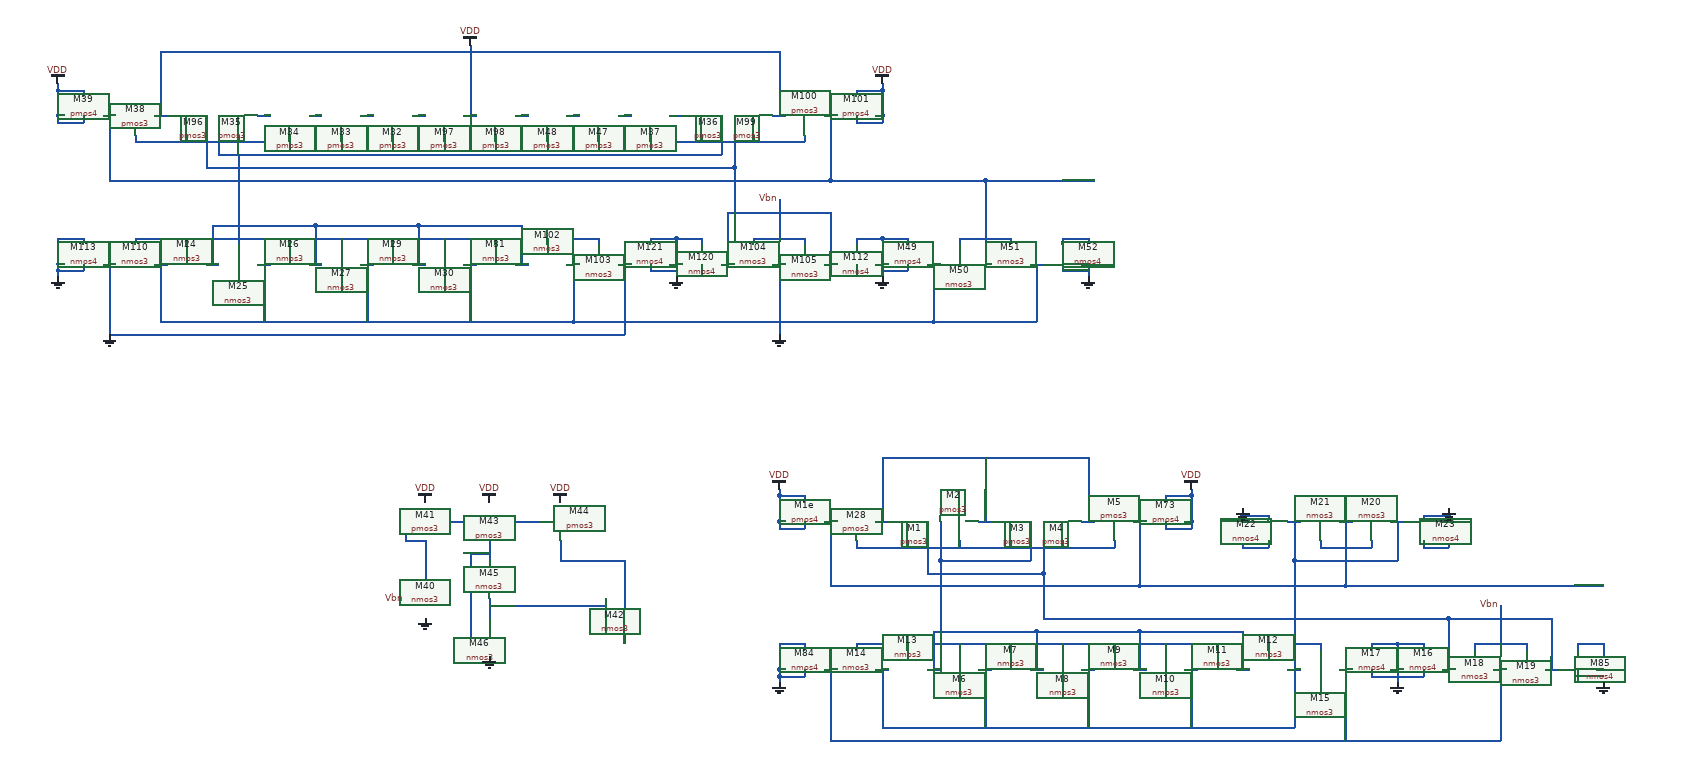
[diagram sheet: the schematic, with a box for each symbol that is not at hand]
v {xschem version=3.4.3 file_version=1.2
}
G {}
K {}
V {}
S {}
E {}
N 140 -240 140 -180 {
lab=#net1}
N 110 -240 140 -240 {
lab=#net1}
N 110 -270 110 -240 {
lab=#net1}
N 110 -270 210 -270 {
lab=#net1}
N 210 -270 320 -270 {
lab=#net1}
N 240 -240 240 -210 {
lab=#net2}
N 240 -150 240 -120 {
lab=#net3}
N 210 -180 210 -90 {
lab=#net2}
N 210 -220 210 -180 {
lab=#net2}
N 210 -220 240 -220 {
lab=#net2}
N 240 -140 420 -140 {
lab=#net3}
N 420 -150 420 -140 {
lab=#net3}
N 350 -240 350 -210 {
lab=#net4}
N 350 -210 420 -210 {
lab=#net4}
N 420 -210 450 -210 {
lab=#net4}
N 450 -210 450 -180 {
lab=#net4}
N 450 -180 450 -80 {
lab=#net4}
N 730 -310 730 -300 {
lab=VDD}
N 690 -310 730 -310 {
lab=VDD}
N 690 -310 690 -270 {
lab=VDD}
N 690 -270 700 -270 {
lab=VDD}
N 730 -270 730 -260 {
lab=VDD}
N 690 -260 730 -260 {
lab=VDD}
N 690 -270 690 -260 {
lab=VDD}
N 690 -320 690 -310 {
lab=VDD}
N 760 -270 780 -270 {
lab=#net5}
N 840 -270 860 -270 {
lab=#net6}
N 1000 -270 1020 -270 {
lab=#net6}
N 1160 -270 1180 -270 {
lab=#net6}
N 1240 -270 1260 -270 {
lab=#net5}
N 1290 -310 1290 -300 {
lab=VDD}
N 1290 -310 1330 -310 {
lab=VDD}
N 1330 -310 1330 -270 {
lab=VDD}
N 1320 -270 1330 -270 {
lab=VDD}
N 1290 -270 1290 -260 {
lab=VDD}
N 1290 -260 1330 -260 {
lab=VDD}
N 1330 -270 1330 -260 {
lab=VDD}
N 1330 -320 1330 -310 {
lab=VDD}
N 810 -240 810 -230 {
lab=#net7}
N 810 -230 1210 -230 {
lab=#net7}
N 1210 -240 1210 -230 {
lab=#net7}
N 1130 -240 1130 -230 {
lab=#net7}
N 1050 -240 1050 -230 {
lab=#net7}
N 970 -240 970 -230 {
lab=#net7}
N 890 -240 890 -230 {
lab=#net7}
N 850 -370 850 -270 {
lab=#net6}
N 1170 -370 1170 -270 {
lab=#net6}
N 1010 -370 1010 -270 {
lab=#net6}
N 920 -270 920 -210 {
lab=#net8}
N 940 -270 940 -210 {
lab=#net9}
N 1080 -270 1080 -210 {
lab=#net9}
N 1100 -270 1100 -210 {
lab=#net8}
N 770 -270 770 -210 {
lab=#net5}
N 970 -80 970 -70 {
lab=#net10}
N 1370 -80 1370 -70 {
lab=#net10}
N 1290 -80 1290 -70 {
lab=#net10}
N 1210 -80 1210 -70 {
lab=#net10}
N 1130 -80 1130 -70 {
lab=#net10}
N 1050 -80 1050 -70 {
lab=#net10}
N 1160 -40 1180 -40 {
lab=#net11}
N 1080 -40 1100 -40 {
lab=#net9}
N 1240 -40 1260 -40 {
lab=#net9}
N 1320 -40 1340 -40 {
lab=#net11}
N 1000 -40 1020 -40 {
lab=#net11}
N 920 -40 940 -40 {
lab=#net9}
N 1400 -40 1420 -40 {
lab=#net9}
N 1450 -80 1450 -70 {
lab=#net10}
N 890 -80 890 -70 {
lab=#net10}
N 1530 -80 1530 -70 {
lab=#net10}
N 810 -80 1530 -80 {
lab=#net10}
N 810 -80 810 -70 {
lab=#net10}
N 930 -100 930 -40 {
lab=#net9}
N 930 -100 1090 -100 {
lab=#net9}
N 1090 -100 1090 -40 {
lab=#net9}
N 1090 -100 1250 -100 {
lab=#net9}
N 1250 -100 1250 -40 {
lab=#net9}
N 1250 -100 1410 -100 {
lab=#net9}
N 1410 -100 1410 -40 {
lab=#net9}
N 1170 -40 1170 50 {
lab=#net11}
N 1330 -40 1330 50 {
lab=#net11}
N 1010 -40 1010 50 {
lab=#net11}
N 840 -40 860 -40 {
lab=#net11}
N 850 -40 850 50 {
lab=#net11}
N 850 50 1490 50 {
lab=#net11}
N 1490 -40 1490 50 {
lab=#net11}
N 1480 -40 1500 -40 {
lab=#net11}
N 850 -370 1170 -370 {
lab=#net6}
N 940 -210 1080 -210 {
lab=#net9}
N 920 -210 920 -190 {
lab=#net8}
N 920 -190 1100 -190 {
lab=#net8}
N 1100 -210 1100 -190 {
lab=#net8}
N 770 -210 770 -170 {
lab=#net5}
N 770 -170 1250 -170 {
lab=#net5}
N 1250 -270 1250 -170 {
lab=#net5}
N 1880 -40 1900 -40 {
lab=#net8}
N 1930 -80 1930 -70 {
lab=GND}
N 1930 -80 1970 -80 {
lab=GND}
N 1960 -40 1970 -40 {
lab=GND}
N 1930 -40 1930 -30 {
lab=GND}
N 1930 -30 1970 -30 {
lab=GND}
N 1970 -80 1970 -20 {
lab=GND}
N 760 -40 780 -40 {
lab=#net12}
N 730 -40 730 -30 {
lab=GND}
N 690 -30 730 -30 {
lab=GND}
N 690 -40 690 -30 {
lab=GND}
N 690 -40 700 -40 {
lab=GND}
N 730 -80 730 -70 {
lab=GND}
N 690 -80 730 -80 {
lab=GND}
N 690 -80 690 -40 {
lab=GND}
N 690 -30 690 -20 {
lab=GND}
N 1480 -270 1500 -270 {
lab=#net11}
N 1450 -240 1450 -230 {
lab=GND}
N 1410 -230 1450 -230 {
lab=GND}
N 1450 -280 1450 -270 {
lab=GND}
N 1410 -280 1450 -280 {
lab=GND}
N 1410 -280 1410 -230 {
lab=GND}
N 1410 -270 1420 -270 {
lab=GND}
N 1410 -290 1410 -280 {
lab=GND}
N 1690 -240 1690 -230 {
lab=GND}
N 1690 -230 1730 -230 {
lab=GND}
N 1730 -280 1730 -230 {
lab=GND}
N 1720 -270 1730 -270 {
lab=GND}
N 1690 -280 1690 -270 {
lab=GND}
N 1690 -280 1730 -280 {
lab=GND}
N 1730 -290 1730 -280 {
lab=GND}
N 1640 -270 1660 -270 {
lab=#net11}
N 1560 -270 1580 -270 {
lab=#net5}
N 1610 -240 1610 -230 {
lab=#net5}
N 1530 -240 1530 -230 {
lab=#net5}
N 1530 -230 1610 -230 {
lab=#net5}
N 1570 -270 1570 -230 {
lab=#net5}
N 1490 -270 1490 -210 {
lab=#net11}
N 1490 -210 1650 -210 {
lab=#net11}
N 1650 -270 1650 -210 {
lab=#net11}
N 1490 -210 1490 -40 {
lab=#net11}
N 1250 -170 1570 -170 {
lab=#net5}
N 1570 -230 1570 -170 {
lab=#net5}
N 940 -210 940 -100 {
lab=#net9}
N 1720 -40 1740 -40 {
lab=#net8}
N 1690 -40 1690 -30 {
lab=GND}
N 1650 -30 1690 -30 {
lab=GND}
N 1650 -40 1660 -40 {
lab=GND}
N 1690 -80 1690 -70 {
lab=GND}
N 1650 -80 1690 -80 {
lab=GND}
N 1800 -40 1820 -40 {
lab=#net12}
N 1770 -80 1770 -70 {
lab=Vbn}
N 1770 -80 1850 -80 {
lab=Vbn}
N 1850 -80 1850 -70 {
lab=Vbn}
N 1560 -40 1580 -40 {
lab=#net12}
N 1610 -80 1610 -70 {
lab=GND}
N 1610 -80 1650 -80 {
lab=GND}
N 1640 -40 1650 -40 {
lab=GND}
N 1610 -40 1610 -30 {
lab=GND}
N 1610 -30 1650 -30 {
lab=GND}
N 1650 -80 1650 -20 {
lab=GND}
N 770 -40 770 70 {
lab=#net12}
N 770 70 1810 70 {
lab=#net12}
N 1810 -40 1810 70 {
lab=#net12}
N 1570 -40 1570 70 {
lab=#net12}
N 1100 -190 1100 -120 {
lab=#net8}
N 1100 -120 1730 -120 {
lab=#net8}
N 1730 -120 1730 -40 {
lab=#net8}
N 1730 -120 1890 -120 {
lab=#net8}
N 1890 -120 1890 -40 {
lab=#net8}
N 1810 -140 1810 -80 {
lab=Vbn}
N 1570 -170 1970 -170 {
lab=#net5}
N -390 -940 -390 -930 {
lab=VDD}
N -430 -940 -390 -940 {
lab=VDD}
N -430 -940 -430 -900 {
lab=VDD}
N -430 -900 -420 -900 {
lab=VDD}
N -390 -900 -390 -890 {
lab=VDD}
N -430 -890 -390 -890 {
lab=VDD}
N -430 -900 -430 -890 {
lab=VDD}
N -430 -950 -430 -940 {
lab=VDD}
N -360 -900 -340 -900 {
lab=#net13}
N -280 -900 -260 -900 {
lab=#net14}
N 200 -900 220 -900 {
lab=#net14}
N 680 -900 700 -900 {
lab=#net14}
N 760 -900 780 -900 {
lab=#net13}
N 810 -940 810 -930 {
lab=VDD}
N 810 -940 850 -940 {
lab=VDD}
N 850 -940 850 -900 {
lab=VDD}
N 840 -900 850 -900 {
lab=VDD}
N 810 -900 810 -890 {
lab=VDD}
N 810 -890 850 -890 {
lab=VDD}
N 850 -900 850 -890 {
lab=VDD}
N 850 -950 850 -940 {
lab=VDD}
N -310 -870 -310 -860 {
lab=#net15}
N 730 -870 730 -860 {
lab=#net15}
N 650 -870 650 -860 {
lab=#net15}
N 250 -870 250 -860 {
lab=#net15}
N 170 -870 170 -860 {
lab=#net15}
N -230 -870 -230 -860 {
lab=#net15}
N -270 -1000 -270 -900 {
lab=#net14}
N 690 -1000 690 -900 {
lab=#net14}
N 210 -1000 210 -900 {
lab=#net14}
N -200 -900 -200 -840 {
lab=#net15}
N -180 -900 -180 -840 {
lab=#net16}
N 620 -900 620 -840 {
lab=#net15}
N -350 -900 -350 -840 {
lab=#net13}
N -150 -710 -150 -700 {
lab=#net16}
N 250 -710 250 -700 {
lab=#net16}
N 170 -710 170 -700 {
lab=#net16}
N 90 -710 90 -700 {
lab=#net16}
N 10 -710 10 -700 {
lab=#net16}
N -70 -710 -70 -700 {
lab=#net16}
N 40 -670 60 -670 {
lab=#net17}
N -40 -670 -20 -670 {
lab=#net16}
N 120 -670 140 -670 {
lab=#net16}
N 200 -670 220 -670 {
lab=#net17}
N -120 -670 -100 -670 {
lab=#net17}
N -200 -670 -180 -670 {
lab=#net16}
N 280 -670 300 -670 {
lab=#net16}
N 330 -710 330 -700 {
lab=#net16}
N -230 -710 -230 -700 {
lab=#net16}
N 410 -710 410 -700 {
lab=#net16}
N -310 -710 410 -710 {
lab=#net16}
N -310 -710 -310 -700 {
lab=#net16}
N -190 -730 -190 -670 {
lab=#net16}
N -190 -730 -30 -730 {
lab=#net16}
N -30 -730 -30 -670 {
lab=#net16}
N -30 -730 130 -730 {
lab=#net16}
N 130 -730 130 -670 {
lab=#net16}
N 130 -730 290 -730 {
lab=#net16}
N 290 -730 290 -670 {
lab=#net16}
N 50 -670 50 -580 {
lab=#net17}
N 210 -670 210 -580 {
lab=#net17}
N -110 -670 -110 -580 {
lab=#net17}
N -280 -670 -260 -670 {
lab=#net17}
N -270 -670 -270 -580 {
lab=#net17}
N -270 -580 370 -580 {
lab=#net17}
N 370 -670 370 -580 {
lab=#net17}
N 360 -670 380 -670 {
lab=#net17}
N -200 -840 -200 -820 {
lab=#net15}
N 620 -840 620 -820 {
lab=#net15}
N -350 -840 -350 -800 {
lab=#net13}
N 770 -900 770 -800 {
lab=#net13}
N 760 -670 780 -670 {
lab=#net15}
N 810 -710 810 -700 {
lab=GND}
N 810 -710 850 -710 {
lab=GND}
N 840 -670 850 -670 {
lab=GND}
N 810 -670 810 -660 {
lab=GND}
N 810 -660 850 -660 {
lab=GND}
N 850 -710 850 -650 {
lab=GND}
N -360 -670 -340 -670 {
lab=GND}
N -390 -670 -390 -660 {
lab=GND}
N -430 -660 -390 -660 {
lab=GND}
N -430 -670 -430 -660 {
lab=GND}
N -430 -670 -420 -670 {
lab=GND}
N -390 -710 -390 -700 {
lab=GND}
N -430 -710 -390 -710 {
lab=GND}
N -430 -710 -430 -670 {
lab=GND}
N -430 -660 -430 -650 {
lab=GND}
N 600 -670 620 -670 {
lab=#net15}
N 570 -670 570 -660 {
lab=GND}
N 530 -660 570 -660 {
lab=GND}
N 530 -670 540 -670 {
lab=GND}
N 570 -710 570 -700 {
lab=GND}
N 530 -710 570 -710 {
lab=GND}
N 680 -670 700 -670 {
lab=GND}
N 650 -710 650 -700 {
lab=Vbn}
N 650 -710 730 -710 {
lab=Vbn}
N 730 -710 730 -700 {
lab=Vbn}
N 440 -670 460 -670 {
lab=GND}
N 490 -710 490 -700 {
lab=GND}
N 490 -710 530 -710 {
lab=GND}
N 520 -670 530 -670 {
lab=GND}
N 490 -670 490 -660 {
lab=GND}
N 490 -660 530 -660 {
lab=GND}
N 530 -710 530 -650 {
lab=GND}
N -350 -670 -350 -560 {
lab=GND}
N 690 -670 690 -560 {
lab=GND}
N 450 -670 450 -560 {
lab=GND}
N 620 -820 620 -750 {
lab=#net15}
N 610 -750 610 -670 {
lab=#net15}
N 610 -750 770 -750 {
lab=#net15}
N 770 -750 770 -670 {
lab=#net15}
N 690 -770 690 -710 {
lab=Vbn}
N -150 -730 -150 -710 {
lab=#net16}
N 10 -870 10 -860 {
lab=#net15}
N 90 -870 90 -860 {
lab=#net15}
N -70 -870 -70 -860 {
lab=#net15}
N -150 -870 -150 -860 {
lab=#net15}
N 490 -870 490 -860 {
lab=#net15}
N 570 -870 570 -860 {
lab=#net15}
N 410 -870 410 -860 {
lab=#net15}
N 330 -870 330 -860 {
lab=#net15}
N 280 -900 300 -900 {
lab=#net18}
N 360 -900 380 -900 {
lab=#net19}
N 440 -900 460 -900 {
lab=#net20}
N 520 -900 540 -900 {
lab=#net21}
N 120 -900 140 -900 {
lab=#net22}
N 40 -900 60 -900 {
lab=#net23}
N -40 -900 -20 -900 {
lab=#net24}
N -120 -900 -100 -900 {
lab=#net25}
N 600 -900 600 -840 {
lab=#net16}
N -180 -840 600 -840 {
lab=#net16}
N -200 -820 620 -820 {
lab=#net15}
N -350 -800 770 -800 {
lab=#net13}
N -270 -1000 690 -1000 {
lab=#net14}
N 890 -670 890 -660 {
lab=GND}
N 850 -660 890 -660 {
lab=GND}
N 850 -670 860 -670 {
lab=GND}
N 890 -710 890 -700 {
lab=GND}
N 850 -710 890 -710 {
lab=GND}
N 1080 -670 1100 -670 {
lab=#net17}
N 1130 -710 1130 -700 {
lab=GND}
N 1130 -710 1170 -710 {
lab=GND}
N 1160 -670 1170 -670 {
lab=GND}
N 1130 -670 1130 -660 {
lab=GND}
N 1130 -660 1170 -660 {
lab=GND}
N 1170 -710 1170 -650 {
lab=GND}
N 920 -670 940 -670 {
lab=#net17}
N 1000 -670 1020 -670 {
lab=#net13}
N 970 -710 970 -700 {
lab=#net13}
N 970 -710 1050 -710 {
lab=#net13}
N 1050 -710 1050 -700 {
lab=#net13}
N 1010 -710 1010 -670 {
lab=#net13}
N 1010 -800 1010 -710 {
lab=#net13}
N 770 -800 1010 -800 {
lab=#net13}
N 1010 -800 1180 -800 {
lab=#net13}
N -150 -840 -150 -730 {
lab=#net16}
N -310 -860 620 -860 {
lab=#net15}
N 620 -860 730 -860 {
lab=#net15}
N 930 -670 930 -580 {
lab=#net17}
N 930 -580 1090 -580 {
lab=#net17}
N 1090 -670 1090 -580 {
lab=#net17}
N 370 -580 930 -580 {
lab=#net17}
N -350 -560 450 -560 {
lab=GND}
N 210 -1010 210 -1000 {}
C {madvlsi/nmos3.sym} 140 -150 0 0 {name=M40
L=\{L\}
W=\{W\}
body=GND
nf=1
mult=1
ad="'int((nf+1)/2) * W/nf * 0.29'" 
pd="'2*int((nf+1)/2) * (W/nf + 0.29)'"
as="'int((nf+2)/2) * W/nf * 0.29'" 
ps="'2*int((nf+2)/2) * (W/nf + 0.29)'"
nrd="'0.29 / W'" nrs="'0.29 / W'"
sa=0 sb=0 sd=0
model=nfet_01v8
spiceprefix=X
}
C {madvlsi/pmos3.sym} 140 -270 0 0 {name=M41
L=\{L\}
W=\{W\}
body=VDD
nf=1
mult=1
ad="'int((nf+1)/2) * W/nf * 0.29'" 
pd="'2*int((nf+1)/2) * (W/nf + 0.29)'"
as="'int((nf+2)/2) * W/nf * 0.29'" 
ps="'2*int((nf+2)/2) * (W/nf + 0.29)'"
nrd="'0.29 / W'" nrs="'0.29 / W'"
sa=0 sb=0 sd=0
model=pfet_01v8
spiceprefix=X
}
C {madvlsi/nmos3.sym} 420 -180 2 0 {name=M42
L=\{L\}
W=\{W\}
body=GND
nf=1
mult=1
ad="'int((nf+1)/2) * W/nf * 0.29'" 
pd="'2*int((nf+1)/2) * (W/nf + 0.29)'"
as="'int((nf+2)/2) * W/nf * 0.29'" 
ps="'2*int((nf+2)/2) * (W/nf + 0.29)'"
nrd="'0.29 / W'" nrs="'0.29 / W'"
sa=0 sb=0 sd=0
model=nfet_01v8
spiceprefix=X
}
C {madvlsi/pmos3.sym} 240 -270 0 0 {name=M43
L=\{L\}
W=\{W\}
body=VDD
nf=1
mult=1/5
ad="'int((nf+1)/2) * W/nf * 0.29'" 
pd="'2*int((nf+1)/2) * (W/nf + 0.29)'"
as="'int((nf+2)/2) * W/nf * 0.29'" 
ps="'2*int((nf+2)/2) * (W/nf + 0.29)'"
nrd="'0.29 / W'" nrs="'0.29 / W'"
sa=0 sb=0 sd=0
model=pfet_01v8
spiceprefix=X
}
C {madvlsi/pmos3.sym} 350 -270 0 0 {name=M44
L=\{L\}
W=\{W\}
body=VDD
nf=1
mult=1
ad="'int((nf+1)/2) * W/nf * 0.29'" 
pd="'2*int((nf+1)/2) * (W/nf + 0.29)'"
as="'int((nf+2)/2) * W/nf * 0.29'" 
ps="'2*int((nf+2)/2) * (W/nf + 0.29)'"
nrd="'0.29 / W'" nrs="'0.29 / W'"
sa=0 sb=0 sd=0
model=pfet_01v8
spiceprefix=X
}
C {madvlsi/nmos3.sym} 240 -180 0 0 {name=M45
L=\{L\}
W=\{W\}
body=GND
nf=1
mult=4
ad="'int((nf+1)/2) * W/nf * 0.29'" 
pd="'2*int((nf+1)/2) * (W/nf + 0.29)'"
as="'int((nf+2)/2) * W/nf * 0.29'" 
ps="'2*int((nf+2)/2) * (W/nf + 0.29)'"
nrd="'0.29 / W'" nrs="'0.29 / W'"
sa=0 sb=0 sd=0
model=nfet_01v8
spiceprefix=X
}
C {madvlsi/nmos3.sym} 240 -90 0 0 {name=M46
L=\{L\}
W=\{W\}
body=GND
nf=1
mult=1
ad="'int((nf+1)/2) * W/nf * 0.29'" 
pd="'2*int((nf+1)/2) * (W/nf + 0.29)'"
as="'int((nf+2)/2) * W/nf * 0.29'" 
ps="'2*int((nf+2)/2) * (W/nf + 0.29)'"
nrd="'0.29 / W'" nrs="'0.29 / W'"
sa=0 sb=0 sd=0
model=nfet_01v8
spiceprefix=X
}
C {madvlsi/gnd.sym} 240 -60 0 0 {name=l25 lab=GND}
C {madvlsi/gnd.sym} 140 -120 0 0 {name=l26 lab=GND}
C {madvlsi/vdd.sym} 140 -300 0 0 {name=l27 lab=VDD}
C {madvlsi/vdd.sym} 240 -300 0 0 {name=l31 lab=VDD}
C {madvlsi/vdd.sym} 350 -300 0 0 {name=l32 lab=VDD}
C {devices/lab_pin.sym} 110 -150 0 0 {name=p29 sig_type=std_logic lab=Vbn
}
C {madvlsi/pmos3.sym} 810 -270 3 0 {name=M28
L=\{L\}
W=\{W/2\}
body=VDD
nf=1
mult=1
ad="'int((nf+1)/2) * W/nf * 0.29'" 
pd="'2*int((nf+1)/2) * (W/nf + 0.29)'"
as="'int((nf+2)/2) * W/nf * 0.29'" 
ps="'2*int((nf+2)/2) * (W/nf + 0.29)'"
nrd="'0.29 / W'" nrs="'0.29 / W'"
sa=0 sb=0 sd=0
model=pfet_01v8
spiceprefix=X
}
C {madvlsi/pmos4.sym} 730 -270 1 0 {name=M1e
L=\{L\}
W=\{W/2\}
nf=1
mult=1
ad="'int((nf+1)/2) * W/nf * 0.29'" 
pd="'2*int((nf+1)/2) * (W/nf + 0.29)'"
as="'int((nf+2)/2) * W/nf * 0.29'" 
ps="'2*int((nf+2)/2) * (W/nf + 0.29)'"
nrd="'0.29 / W'" nrs="'0.29 / W'"
sa=0 sb=0 sd=0
model=pfet_01v8
spiceprefix=X
}
C {madvlsi/vdd.sym} 690 -320 0 0 {name=l24 lab=VDD}
C {madvlsi/pmos3.sym} 890 -270 3 0 {name=M1
L=\{L\}
W=\{W/2\}
body=VDD
nf=1
mult=1
ad="'int((nf+1)/2) * W/nf * 0.29'" 
pd="'2*int((nf+1)/2) * (W/nf + 0.29)'"
as="'int((nf+2)/2) * W/nf * 0.29'" 
ps="'2*int((nf+2)/2) * (W/nf + 0.29)'"
nrd="'0.29 / W'" nrs="'0.29 / W'"
sa=0 sb=0 sd=0
model=pfet_01v8
spiceprefix=X
}
C {madvlsi/pmos3.sym} 970 -270 3 0 {name=M2
L=\{L\}
W=\{W/2\}
body=VDD
nf=1
mult=1
ad="'int((nf+1)/2) * W/nf * 0.29'" 
pd="'2*int((nf+1)/2) * (W/nf + 0.29)'"
as="'int((nf+2)/2) * W/nf * 0.29'" 
ps="'2*int((nf+2)/2) * (W/nf + 0.29)'"
nrd="'0.29 / W'" nrs="'0.29 / W'"
sa=0 sb=0 sd=0
model=pfet_01v8
spiceprefix=X
}
C {madvlsi/pmos3.sym} 1050 -270 3 0 {name=M3
L=\{L\}
W=\{W/2\}
body=VDD
nf=1
mult=1
ad="'int((nf+1)/2) * W/nf * 0.29'" 
pd="'2*int((nf+1)/2) * (W/nf + 0.29)'"
as="'int((nf+2)/2) * W/nf * 0.29'" 
ps="'2*int((nf+2)/2) * (W/nf + 0.29)'"
nrd="'0.29 / W'" nrs="'0.29 / W'"
sa=0 sb=0 sd=0
model=pfet_01v8
spiceprefix=X
}
C {madvlsi/pmos3.sym} 1130 -270 3 0 {name=M4
L=\{L\}
W=\{W/2\}
body=VDD
nf=1
mult=1
ad="'int((nf+1)/2) * W/nf * 0.29'" 
pd="'2*int((nf+1)/2) * (W/nf + 0.29)'"
as="'int((nf+2)/2) * W/nf * 0.29'" 
ps="'2*int((nf+2)/2) * (W/nf + 0.29)'"
nrd="'0.29 / W'" nrs="'0.29 / W'"
sa=0 sb=0 sd=0
model=pfet_01v8
spiceprefix=X
}
C {madvlsi/pmos3.sym} 1210 -270 3 0 {name=M5
L=\{L\}
W=\{W/2\}
body=VDD
nf=1
mult=1
ad="'int((nf+1)/2) * W/nf * 0.29'" 
pd="'2*int((nf+1)/2) * (W/nf + 0.29)'"
as="'int((nf+2)/2) * W/nf * 0.29'" 
ps="'2*int((nf+2)/2) * (W/nf + 0.29)'"
nrd="'0.29 / W'" nrs="'0.29 / W'"
sa=0 sb=0 sd=0
model=pfet_01v8
spiceprefix=X
}
C {madvlsi/vdd.sym} 1330 -320 0 0 {name=l35 lab=VDD}
C {madvlsi/pmos4.sym} 1290 -270 1 0 {name=M73
L=\{L\}
W=\{W/2\}
nf=1
mult=1
ad="'int((nf+1)/2) * W/nf * 0.29'" 
pd="'2*int((nf+1)/2) * (W/nf + 0.29)'"
as="'int((nf+2)/2) * W/nf * 0.29'" 
ps="'2*int((nf+2)/2) * (W/nf + 0.29)'"
nrd="'0.29 / W'" nrs="'0.29 / W'"
sa=0 sb=0 sd=0
model=pfet_01v8
spiceprefix=X
}
C {madvlsi/nmos3.sym} 970 -40 1 0 {name=M6
L=\{L\}
W=\{W\}
body=GND
nf=1
mult=1
ad="'int((nf+1)/2) * W/nf * 0.29'" 
pd="'2*int((nf+1)/2) * (W/nf + 0.29)'"
as="'int((nf+2)/2) * W/nf * 0.29'" 
ps="'2*int((nf+2)/2) * (W/nf + 0.29)'"
nrd="'0.29 / W'" nrs="'0.29 / W'"
sa=0 sb=0 sd=0
model=nfet_01v8
spiceprefix=X
}
C {madvlsi/nmos3.sym} 1050 -40 1 0 {name=M7
L=\{L\}
W=\{W\}
body=GND
nf=1
mult=1
ad="'int((nf+1)/2) * W/nf * 0.29'" 
pd="'2*int((nf+1)/2) * (W/nf + 0.29)'"
as="'int((nf+2)/2) * W/nf * 0.29'" 
ps="'2*int((nf+2)/2) * (W/nf + 0.29)'"
nrd="'0.29 / W'" nrs="'0.29 / W'"
sa=0 sb=0 sd=0
model=nfet_01v8
spiceprefix=X
}
C {madvlsi/nmos3.sym} 1130 -40 1 0 {name=M8
L=\{L\}
W=\{W\}
body=GND
nf=1
mult=1
ad="'int((nf+1)/2) * W/nf * 0.29'" 
pd="'2*int((nf+1)/2) * (W/nf + 0.29)'"
as="'int((nf+2)/2) * W/nf * 0.29'" 
ps="'2*int((nf+2)/2) * (W/nf + 0.29)'"
nrd="'0.29 / W'" nrs="'0.29 / W'"
sa=0 sb=0 sd=0
model=nfet_01v8
spiceprefix=X
}
C {madvlsi/nmos3.sym} 1210 -40 1 0 {name=M9
L=\{L\}
W=\{W\}
body=GND
nf=1
mult=1
ad="'int((nf+1)/2) * W/nf * 0.29'" 
pd="'2*int((nf+1)/2) * (W/nf + 0.29)'"
as="'int((nf+2)/2) * W/nf * 0.29'" 
ps="'2*int((nf+2)/2) * (W/nf + 0.29)'"
nrd="'0.29 / W'" nrs="'0.29 / W'"
sa=0 sb=0 sd=0
model=nfet_01v8
spiceprefix=X
}
C {madvlsi/nmos3.sym} 1290 -40 1 0 {name=M10
L=\{L\}
W=\{W\}
body=GND
nf=1
mult=1
ad="'int((nf+1)/2) * W/nf * 0.29'" 
pd="'2*int((nf+1)/2) * (W/nf + 0.29)'"
as="'int((nf+2)/2) * W/nf * 0.29'" 
ps="'2*int((nf+2)/2) * (W/nf + 0.29)'"
nrd="'0.29 / W'" nrs="'0.29 / W'"
sa=0 sb=0 sd=0
model=nfet_01v8
spiceprefix=X
}
C {madvlsi/nmos3.sym} 1370 -40 1 0 {name=M11
L=\{L\}
W=\{W\}
body=GND
nf=1
mult=1
ad="'int((nf+1)/2) * W/nf * 0.29'" 
pd="'2*int((nf+1)/2) * (W/nf + 0.29)'"
as="'int((nf+2)/2) * W/nf * 0.29'" 
ps="'2*int((nf+2)/2) * (W/nf + 0.29)'"
nrd="'0.29 / W'" nrs="'0.29 / W'"
sa=0 sb=0 sd=0
model=nfet_01v8
spiceprefix=X
}
C {madvlsi/nmos3.sym} 1450 -40 1 0 {name=M12
L=\{L\}
W=\{W\}
body=GND
nf=1
mult=1
ad="'int((nf+1)/2) * W/nf * 0.29'" 
pd="'2*int((nf+1)/2) * (W/nf + 0.29)'"
as="'int((nf+2)/2) * W/nf * 0.29'" 
ps="'2*int((nf+2)/2) * (W/nf + 0.29)'"
nrd="'0.29 / W'" nrs="'0.29 / W'"
sa=0 sb=0 sd=0
model=nfet_01v8
spiceprefix=X
}
C {madvlsi/nmos3.sym} 890 -40 1 0 {name=M13
L=\{L\}
W=\{W\}
body=GND
nf=1
mult=1
ad="'int((nf+1)/2) * W/nf * 0.29'" 
pd="'2*int((nf+1)/2) * (W/nf + 0.29)'"
as="'int((nf+2)/2) * W/nf * 0.29'" 
ps="'2*int((nf+2)/2) * (W/nf + 0.29)'"
nrd="'0.29 / W'" nrs="'0.29 / W'"
sa=0 sb=0 sd=0
model=nfet_01v8
spiceprefix=X
}
C {madvlsi/nmos3.sym} 810 -40 1 0 {name=M14
L=\{L\}
W=\{W\}
body=GND
nf=1
mult=1
ad="'int((nf+1)/2) * W/nf * 0.29'" 
pd="'2*int((nf+1)/2) * (W/nf + 0.29)'"
as="'int((nf+2)/2) * W/nf * 0.29'" 
ps="'2*int((nf+2)/2) * (W/nf + 0.29)'"
nrd="'0.29 / W'" nrs="'0.29 / W'"
sa=0 sb=0 sd=0
model=nfet_01v8
spiceprefix=X
}
C {madvlsi/nmos3.sym} 1530 -40 1 0 {name=M15
L=\{L\}
W=\{W\}
body=GND
nf=1
mult=1
ad="'int((nf+1)/2) * W/nf * 0.29'" 
pd="'2*int((nf+1)/2) * (W/nf + 0.29)'"
as="'int((nf+2)/2) * W/nf * 0.29'" 
ps="'2*int((nf+2)/2) * (W/nf + 0.29)'"
nrd="'0.29 / W'" nrs="'0.29 / W'"
sa=0 sb=0 sd=0
model=nfet_01v8
spiceprefix=X
}
C {madvlsi/nmos4.sym} 1930 -40 1 0 {name=M85
L=\{L\}
W=\{W/2\}
nf=1 
mult=1
ad="'int((nf+1)/2) * W/nf * 0.29'" 
pd="'2*int((nf+1)/2) * (W/nf + 0.29)'"
as="'int((nf+2)/2) * W/nf * 0.29'" 
ps="'2*int((nf+2)/2) * (W/nf + 0.29)'"
nrd="'0.29 / W'" nrs="'0.29 / W'"
sa=0 sb=0 sd=0
model=nfet_01v8
spiceprefix=X
}
C {madvlsi/gnd.sym} 1970 -20 0 0 {name=l38 lab=GND}
C {madvlsi/gnd.sym} 690 -20 0 0 {name=l37 lab=GND}
C {madvlsi/nmos4.sym} 730 -40 1 0 {name=M84
L=\{L\}
W=\{W/2\}
nf=1 
mult=1
ad="'int((nf+1)/2) * W/nf * 0.29'" 
pd="'2*int((nf+1)/2) * (W/nf + 0.29)'"
as="'int((nf+2)/2) * W/nf * 0.29'" 
ps="'2*int((nf+2)/2) * (W/nf + 0.29)'"
nrd="'0.29 / W'" nrs="'0.29 / W'"
sa=0 sb=0 sd=0
model=nfet_01v8
spiceprefix=X
}
C {madvlsi/nmos3.sym} 1610 -270 3 0 {name=M20
L=\{L\}
W=\{W\}
body=GND
nf=1
mult=1
ad="'int((nf+1)/2) * W/nf * 0.29'" 
pd="'2*int((nf+1)/2) * (W/nf + 0.29)'"
as="'int((nf+2)/2) * W/nf * 0.29'" 
ps="'2*int((nf+2)/2) * (W/nf + 0.29)'"
nrd="'0.29 / W'" nrs="'0.29 / W'"
sa=0 sb=0 sd=0
model=nfet_01v8
spiceprefix=X
}
C {madvlsi/nmos3.sym} 1530 -270 3 0 {name=M21
L=\{L\}
W=\{W\}
body=GND
nf=1
mult=1
ad="'int((nf+1)/2) * W/nf * 0.29'" 
pd="'2*int((nf+1)/2) * (W/nf + 0.29)'"
as="'int((nf+2)/2) * W/nf * 0.29'" 
ps="'2*int((nf+2)/2) * (W/nf + 0.29)'"
nrd="'0.29 / W'" nrs="'0.29 / W'"
sa=0 sb=0 sd=0
model=nfet_01v8
spiceprefix=X
}
C {madvlsi/nmos4.sym} 1450 -270 3 0 {name=M22
L=\{L\}
W=\{W/2\}
nf=1 
mult=1
ad="'int((nf+1)/2) * W/nf * 0.29'" 
pd="'2*int((nf+1)/2) * (W/nf + 0.29)'"
as="'int((nf+2)/2) * W/nf * 0.29'" 
ps="'2*int((nf+2)/2) * (W/nf + 0.29)'"
nrd="'0.29 / W'" nrs="'0.29 / W'"
sa=0 sb=0 sd=0
model=nfet_01v8
spiceprefix=X
}
C {madvlsi/gnd.sym} 1410 -290 2 0 {name=l1 lab=GND}
C {madvlsi/nmos4.sym} 1690 -270 3 0 {name=M23
L=\{L\}
W=\{W/2\}
nf=1 
mult=1
ad="'int((nf+1)/2) * W/nf * 0.29'" 
pd="'2*int((nf+1)/2) * (W/nf + 0.29)'"
as="'int((nf+2)/2) * W/nf * 0.29'" 
ps="'2*int((nf+2)/2) * (W/nf + 0.29)'"
nrd="'0.29 / W'" nrs="'0.29 / W'"
sa=0 sb=0 sd=0
model=nfet_01v8
spiceprefix=X
}
C {madvlsi/gnd.sym} 1730 -290 2 0 {name=l2 lab=GND}
C {madvlsi/nmos3.sym} 1770 -40 1 0 {name=M18
L=\{L\}
W=\{W\}
body=GND
nf=1
mult=1
ad="'int((nf+1)/2) * W/nf * 0.29'" 
pd="'2*int((nf+1)/2) * (W/nf + 0.29)'"
as="'int((nf+2)/2) * W/nf * 0.29'" 
ps="'2*int((nf+2)/2) * (W/nf + 0.29)'"
nrd="'0.29 / W'" nrs="'0.29 / W'"
sa=0 sb=0 sd=0
model=nfet_01v8
spiceprefix=X
}
C {madvlsi/nmos3.sym} 1850 -40 1 0 {name=M19
L=\{L\}
W=\{W\}
body=GND
nf=1
mult=1
ad="'int((nf+1)/2) * W/nf * 0.29'" 
pd="'2*int((nf+1)/2) * (W/nf + 0.29)'"
as="'int((nf+2)/2) * W/nf * 0.29'" 
ps="'2*int((nf+2)/2) * (W/nf + 0.29)'"
nrd="'0.29 / W'" nrs="'0.29 / W'"
sa=0 sb=0 sd=0
model=nfet_01v8
spiceprefix=X
}
C {madvlsi/nmos4.sym} 1690 -40 1 0 {name=M16
L=\{L\}
W=\{W/2\}
nf=1 
mult=1
ad="'int((nf+1)/2) * W/nf * 0.29'" 
pd="'2*int((nf+1)/2) * (W/nf + 0.29)'"
as="'int((nf+2)/2) * W/nf * 0.29'" 
ps="'2*int((nf+2)/2) * (W/nf + 0.29)'"
nrd="'0.29 / W'" nrs="'0.29 / W'"
sa=0 sb=0 sd=0
model=nfet_01v8
spiceprefix=X
}
C {madvlsi/nmos4.sym} 1610 -40 1 0 {name=M17
L=\{L\}
W=\{W/2\}
nf=1 
mult=1
ad="'int((nf+1)/2) * W/nf * 0.29'" 
pd="'2*int((nf+1)/2) * (W/nf + 0.29)'"
as="'int((nf+2)/2) * W/nf * 0.29'" 
ps="'2*int((nf+2)/2) * (W/nf + 0.29)'"
nrd="'0.29 / W'" nrs="'0.29 / W'"
sa=0 sb=0 sd=0
model=nfet_01v8
spiceprefix=X
}
C {madvlsi/gnd.sym} 1650 -20 0 0 {name=l4 lab=GND}
C {devices/lab_pin.sym} 1810 -140 1 0 {name=p1 sig_type=std_logic lab=Vbn
}
C {madvlsi/pmos3.sym} -310 -900 3 0 {name=M38
L=\{L\}
W=\{W/2\}
body=VDD
nf=1
mult=1
ad="'int((nf+1)/2) * W/nf * 0.29'" 
pd="'2*int((nf+1)/2) * (W/nf + 0.29)'"
as="'int((nf+2)/2) * W/nf * 0.29'" 
ps="'2*int((nf+2)/2) * (W/nf + 0.29)'"
nrd="'0.29 / W'" nrs="'0.29 / W'"
sa=0 sb=0 sd=0
model=pfet_01v8
spiceprefix=X
}
C {madvlsi/pmos4.sym} -390 -900 1 0 {name=M39
L=\{L\}
W=\{W/2\}
nf=1
mult=1
ad="'int((nf+1)/2) * W/nf * 0.29'" 
pd="'2*int((nf+1)/2) * (W/nf + 0.29)'"
as="'int((nf+2)/2) * W/nf * 0.29'" 
ps="'2*int((nf+2)/2) * (W/nf + 0.29)'"
nrd="'0.29 / W'" nrs="'0.29 / W'"
sa=0 sb=0 sd=0
model=pfet_01v8
spiceprefix=X
}
C {madvlsi/vdd.sym} -430 -950 0 0 {name=l3 lab=VDD}
C {madvlsi/pmos3.sym} -230 -900 3 0 {name=M96
L=\{L\}
W=\{W/2\}
body=VDD
nf=1
mult=1
ad="'int((nf+1)/2) * W/nf * 0.29'" 
pd="'2*int((nf+1)/2) * (W/nf + 0.29)'"
as="'int((nf+2)/2) * W/nf * 0.29'" 
ps="'2*int((nf+2)/2) * (W/nf + 0.29)'"
nrd="'0.29 / W'" nrs="'0.29 / W'"
sa=0 sb=0 sd=0
model=pfet_01v8
spiceprefix=X
}
C {madvlsi/pmos3.sym} 170 -900 3 0 {name=M97
L=\{L\}
W=\{W/2\}
body=VDD
nf=1
mult=1
ad="'int((nf+1)/2) * W/nf * 0.29'" 
pd="'2*int((nf+1)/2) * (W/nf + 0.29)'"
as="'int((nf+2)/2) * W/nf * 0.29'" 
ps="'2*int((nf+2)/2) * (W/nf + 0.29)'"
nrd="'0.29 / W'" nrs="'0.29 / W'"
sa=0 sb=0 sd=0
model=pfet_01v8
spiceprefix=X
}
C {madvlsi/pmos3.sym} 250 -900 3 0 {name=M98
L=\{L\}
W=\{W/2\}
body=VDD
nf=1
mult=1
ad="'int((nf+1)/2) * W/nf * 0.29'" 
pd="'2*int((nf+1)/2) * (W/nf + 0.29)'"
as="'int((nf+2)/2) * W/nf * 0.29'" 
ps="'2*int((nf+2)/2) * (W/nf + 0.29)'"
nrd="'0.29 / W'" nrs="'0.29 / W'"
sa=0 sb=0 sd=0
model=pfet_01v8
spiceprefix=X
}
C {madvlsi/pmos3.sym} 650 -900 3 0 {name=M99
L=\{L\}
W=\{W/2\}
body=VDD
nf=1
mult=1
ad="'int((nf+1)/2) * W/nf * 0.29'" 
pd="'2*int((nf+1)/2) * (W/nf + 0.29)'"
as="'int((nf+2)/2) * W/nf * 0.29'" 
ps="'2*int((nf+2)/2) * (W/nf + 0.29)'"
nrd="'0.29 / W'" nrs="'0.29 / W'"
sa=0 sb=0 sd=0
model=pfet_01v8
spiceprefix=X
}
C {madvlsi/pmos3.sym} 730 -900 3 0 {name=M100
L=\{L\}
W=\{W/2\}
body=VDD
nf=1
mult=1
ad="'int((nf+1)/2) * W/nf * 0.29'" 
pd="'2*int((nf+1)/2) * (W/nf + 0.29)'"
as="'int((nf+2)/2) * W/nf * 0.29'" 
ps="'2*int((nf+2)/2) * (W/nf + 0.29)'"
nrd="'0.29 / W'" nrs="'0.29 / W'"
sa=0 sb=0 sd=0
model=pfet_01v8
spiceprefix=X
}
C {madvlsi/vdd.sym} 850 -950 0 0 {name=l5 lab=VDD}
C {madvlsi/pmos4.sym} 810 -900 1 0 {name=M101
L=\{L\}
W=\{W/2\}
nf=1
mult=1
ad="'int((nf+1)/2) * W/nf * 0.29'" 
pd="'2*int((nf+1)/2) * (W/nf + 0.29)'"
as="'int((nf+2)/2) * W/nf * 0.29'" 
ps="'2*int((nf+2)/2) * (W/nf + 0.29)'"
nrd="'0.29 / W'" nrs="'0.29 / W'"
sa=0 sb=0 sd=0
model=pfet_01v8
spiceprefix=X
}
C {madvlsi/nmos3.sym} -310 -670 1 0 {name=M110
L=\{L\}
W=\{W/2\}
body=GND
nf=1
mult=1
ad="'int((nf+1)/2) * W/nf * 0.29'" 
pd="'2*int((nf+1)/2) * (W/nf + 0.29)'"
as="'int((nf+2)/2) * W/nf * 0.29'" 
ps="'2*int((nf+2)/2) * (W/nf + 0.29)'"
nrd="'0.29 / W'" nrs="'0.29 / W'"
sa=0 sb=0 sd=0
model=nfet_01v8
spiceprefix=X
}
C {madvlsi/nmos4.sym} 810 -670 1 0 {name=M112
L=\{L\}
W=\{W/2\}
nf=1 
mult=1
ad="'int((nf+1)/2) * W/nf * 0.29'" 
pd="'2*int((nf+1)/2) * (W/nf + 0.29)'"
as="'int((nf+2)/2) * W/nf * 0.29'" 
ps="'2*int((nf+2)/2) * (W/nf + 0.29)'"
nrd="'0.29 / W'" nrs="'0.29 / W'"
sa=0 sb=0 sd=0
model=nfet_01v8
spiceprefix=X
}
C {madvlsi/gnd.sym} 850 -650 0 0 {name=l6 lab=GND}
C {madvlsi/gnd.sym} -430 -650 0 0 {name=l23 lab=GND}
C {madvlsi/nmos4.sym} -390 -670 1 0 {name=M113
L=\{L\}
W=\{W/2\}
nf=1 
mult=1
ad="'int((nf+1)/2) * W/nf * 0.29'" 
pd="'2*int((nf+1)/2) * (W/nf + 0.29)'"
as="'int((nf+2)/2) * W/nf * 0.29'" 
ps="'2*int((nf+2)/2) * (W/nf + 0.29)'"
nrd="'0.29 / W'" nrs="'0.29 / W'"
sa=0 sb=0 sd=0
model=nfet_01v8
spiceprefix=X
}
C {madvlsi/nmos4.sym} 570 -670 1 0 {name=M120
L=\{L\}
W=\{W/2\}
nf=1 
mult=1
ad="'int((nf+1)/2) * W/nf * 0.29'" 
pd="'2*int((nf+1)/2) * (W/nf + 0.29)'"
as="'int((nf+2)/2) * W/nf * 0.29'" 
ps="'2*int((nf+2)/2) * (W/nf + 0.29)'"
nrd="'0.29 / W'" nrs="'0.29 / W'"
sa=0 sb=0 sd=0
model=nfet_01v8
spiceprefix=X
}
C {madvlsi/nmos4.sym} 490 -670 1 0 {name=M121
L=\{L\}
W=\{W/2\}
nf=1 
mult=1
ad="'int((nf+1)/2) * W/nf * 0.29'" 
pd="'2*int((nf+1)/2) * (W/nf + 0.29)'"
as="'int((nf+2)/2) * W/nf * 0.29'" 
ps="'2*int((nf+2)/2) * (W/nf + 0.29)'"
nrd="'0.29 / W'" nrs="'0.29 / W'"
sa=0 sb=0 sd=0
model=nfet_01v8
spiceprefix=X
}
C {madvlsi/gnd.sym} 530 -650 0 0 {name=l30 lab=GND}
C {devices/lab_pin.sym} 690 -770 1 0 {name=p2 sig_type=std_logic lab=Vbn
}
C {madvlsi/nmos3.sym} -230 -670 1 0 {name=M24
L=\{L\}
W=\{W/2\}
body=GND
nf=1
mult=1
ad="'int((nf+1)/2) * W/nf * 0.29'" 
pd="'2*int((nf+1)/2) * (W/nf + 0.29)'"
as="'int((nf+2)/2) * W/nf * 0.29'" 
ps="'2*int((nf+2)/2) * (W/nf + 0.29)'"
nrd="'0.29 / W'" nrs="'0.29 / W'"
sa=0 sb=0 sd=0
model=nfet_01v8
spiceprefix=X
}
C {madvlsi/nmos3.sym} -150 -670 1 0 {name=M25
L=\{L\}
W=\{W/2\}
body=GND
nf=1
mult=1
ad="'int((nf+1)/2) * W/nf * 0.29'" 
pd="'2*int((nf+1)/2) * (W/nf + 0.29)'"
as="'int((nf+2)/2) * W/nf * 0.29'" 
ps="'2*int((nf+2)/2) * (W/nf + 0.29)'"
nrd="'0.29 / W'" nrs="'0.29 / W'"
sa=0 sb=0 sd=0
model=nfet_01v8
spiceprefix=X
}
C {madvlsi/nmos3.sym} -70 -670 1 0 {name=M26
L=\{L\}
W=\{W/2\}
body=GND
nf=1
mult=1
ad="'int((nf+1)/2) * W/nf * 0.29'" 
pd="'2*int((nf+1)/2) * (W/nf + 0.29)'"
as="'int((nf+2)/2) * W/nf * 0.29'" 
ps="'2*int((nf+2)/2) * (W/nf + 0.29)'"
nrd="'0.29 / W'" nrs="'0.29 / W'"
sa=0 sb=0 sd=0
model=nfet_01v8
spiceprefix=X
}
C {madvlsi/nmos3.sym} 10 -670 1 0 {name=M27
L=\{L\}
W=\{W/2\}
body=GND
nf=1
mult=1
ad="'int((nf+1)/2) * W/nf * 0.29'" 
pd="'2*int((nf+1)/2) * (W/nf + 0.29)'"
as="'int((nf+2)/2) * W/nf * 0.29'" 
ps="'2*int((nf+2)/2) * (W/nf + 0.29)'"
nrd="'0.29 / W'" nrs="'0.29 / W'"
sa=0 sb=0 sd=0
model=nfet_01v8
spiceprefix=X
}
C {madvlsi/nmos3.sym} 90 -670 1 0 {name=M29
L=\{L\}
W=\{W/2\}
body=GND
nf=1
mult=1
ad="'int((nf+1)/2) * W/nf * 0.29'" 
pd="'2*int((nf+1)/2) * (W/nf + 0.29)'"
as="'int((nf+2)/2) * W/nf * 0.29'" 
ps="'2*int((nf+2)/2) * (W/nf + 0.29)'"
nrd="'0.29 / W'" nrs="'0.29 / W'"
sa=0 sb=0 sd=0
model=nfet_01v8
spiceprefix=X
}
C {madvlsi/nmos3.sym} 170 -670 1 0 {name=M30
L=\{L\}
W=\{W/2\}
body=GND
nf=1
mult=1
ad="'int((nf+1)/2) * W/nf * 0.29'" 
pd="'2*int((nf+1)/2) * (W/nf + 0.29)'"
as="'int((nf+2)/2) * W/nf * 0.29'" 
ps="'2*int((nf+2)/2) * (W/nf + 0.29)'"
nrd="'0.29 / W'" nrs="'0.29 / W'"
sa=0 sb=0 sd=0
model=nfet_01v8
spiceprefix=X
}
C {madvlsi/nmos3.sym} 250 -670 1 0 {name=M31
L=\{L\}
W=\{W/2\}
body=GND
nf=1
mult=1
ad="'int((nf+1)/2) * W/nf * 0.29'" 
pd="'2*int((nf+1)/2) * (W/nf + 0.29)'"
as="'int((nf+2)/2) * W/nf * 0.29'" 
ps="'2*int((nf+2)/2) * (W/nf + 0.29)'"
nrd="'0.29 / W'" nrs="'0.29 / W'"
sa=0 sb=0 sd=0
model=nfet_01v8
spiceprefix=X
}
C {madvlsi/nmos3.sym} 330 -670 1 0 {name=M102
L=\{L\}
W=\{W/2\}
body=GND
nf=1
mult=1
ad="'int((nf+1)/2) * W/nf * 0.29'" 
pd="'2*int((nf+1)/2) * (W/nf + 0.29)'"
as="'int((nf+2)/2) * W/nf * 0.29'" 
ps="'2*int((nf+2)/2) * (W/nf + 0.29)'"
nrd="'0.29 / W'" nrs="'0.29 / W'"
sa=0 sb=0 sd=0
model=nfet_01v8
spiceprefix=X
}
C {madvlsi/nmos3.sym} 410 -670 1 0 {name=M103
L=\{L\}
W=\{W/2\}
body=GND
nf=1
mult=1
ad="'int((nf+1)/2) * W/nf * 0.29'" 
pd="'2*int((nf+1)/2) * (W/nf + 0.29)'"
as="'int((nf+2)/2) * W/nf * 0.29'" 
ps="'2*int((nf+2)/2) * (W/nf + 0.29)'"
nrd="'0.29 / W'" nrs="'0.29 / W'"
sa=0 sb=0 sd=0
model=nfet_01v8
spiceprefix=X
}
C {madvlsi/nmos3.sym} 650 -670 1 0 {name=M104
L=\{L\}
W=\{W/2\}
body=GND
nf=1
mult=1
ad="'int((nf+1)/2) * W/nf * 0.29'" 
pd="'2*int((nf+1)/2) * (W/nf + 0.29)'"
as="'int((nf+2)/2) * W/nf * 0.29'" 
ps="'2*int((nf+2)/2) * (W/nf + 0.29)'"
nrd="'0.29 / W'" nrs="'0.29 / W'"
sa=0 sb=0 sd=0
model=nfet_01v8
spiceprefix=X
}
C {madvlsi/nmos3.sym} 730 -670 1 0 {name=M105
L=\{L\}
W=\{W/2\}
body=GND
nf=1
mult=1
ad="'int((nf+1)/2) * W/nf * 0.29'" 
pd="'2*int((nf+1)/2) * (W/nf + 0.29)'"
as="'int((nf+2)/2) * W/nf * 0.29'" 
ps="'2*int((nf+2)/2) * (W/nf + 0.29)'"
nrd="'0.29 / W'" nrs="'0.29 / W'"
sa=0 sb=0 sd=0
model=nfet_01v8
spiceprefix=X
}
C {madvlsi/pmos3.sym} 90 -900 3 0 {name=M32
L=\{L\}
W=\{W/2\}
body=VDD
nf=1
mult=1
ad="'int((nf+1)/2) * W/nf * 0.29'" 
pd="'2*int((nf+1)/2) * (W/nf + 0.29)'"
as="'int((nf+2)/2) * W/nf * 0.29'" 
ps="'2*int((nf+2)/2) * (W/nf + 0.29)'"
nrd="'0.29 / W'" nrs="'0.29 / W'"
sa=0 sb=0 sd=0
model=pfet_01v8
spiceprefix=X
}
C {madvlsi/pmos3.sym} 10 -900 3 0 {name=M33
L=\{L\}
W=\{W/2\}
body=VDD
nf=1
mult=1
ad="'int((nf+1)/2) * W/nf * 0.29'" 
pd="'2*int((nf+1)/2) * (W/nf + 0.29)'"
as="'int((nf+2)/2) * W/nf * 0.29'" 
ps="'2*int((nf+2)/2) * (W/nf + 0.29)'"
nrd="'0.29 / W'" nrs="'0.29 / W'"
sa=0 sb=0 sd=0
model=pfet_01v8
spiceprefix=X
}
C {madvlsi/pmos3.sym} -70 -900 3 0 {name=M34
L=\{L\}
W=\{W/2\}
body=VDD
nf=1
mult=1
ad="'int((nf+1)/2) * W/nf * 0.29'" 
pd="'2*int((nf+1)/2) * (W/nf + 0.29)'"
as="'int((nf+2)/2) * W/nf * 0.29'" 
ps="'2*int((nf+2)/2) * (W/nf + 0.29)'"
nrd="'0.29 / W'" nrs="'0.29 / W'"
sa=0 sb=0 sd=0
model=pfet_01v8
spiceprefix=X
}
C {madvlsi/pmos3.sym} -150 -900 3 0 {name=M35
L=\{L\}
W=\{W/2\}
body=VDD
nf=1
mult=1
ad="'int((nf+1)/2) * W/nf * 0.29'" 
pd="'2*int((nf+1)/2) * (W/nf + 0.29)'"
as="'int((nf+2)/2) * W/nf * 0.29'" 
ps="'2*int((nf+2)/2) * (W/nf + 0.29)'"
nrd="'0.29 / W'" nrs="'0.29 / W'"
sa=0 sb=0 sd=0
model=pfet_01v8
spiceprefix=X
}
C {madvlsi/pmos3.sym} 570 -900 3 0 {name=M36
L=\{L\}
W=\{W/2\}
body=VDD
nf=1
mult=1
ad="'int((nf+1)/2) * W/nf * 0.29'" 
pd="'2*int((nf+1)/2) * (W/nf + 0.29)'"
as="'int((nf+2)/2) * W/nf * 0.29'" 
ps="'2*int((nf+2)/2) * (W/nf + 0.29)'"
nrd="'0.29 / W'" nrs="'0.29 / W'"
sa=0 sb=0 sd=0
model=pfet_01v8
spiceprefix=X
}
C {madvlsi/pmos3.sym} 490 -900 3 0 {name=M37
L=\{L\}
W=\{W/2\}
body=VDD
nf=1
mult=1
ad="'int((nf+1)/2) * W/nf * 0.29'" 
pd="'2*int((nf+1)/2) * (W/nf + 0.29)'"
as="'int((nf+2)/2) * W/nf * 0.29'" 
ps="'2*int((nf+2)/2) * (W/nf + 0.29)'"
nrd="'0.29 / W'" nrs="'0.29 / W'"
sa=0 sb=0 sd=0
model=pfet_01v8
spiceprefix=X
}
C {madvlsi/pmos3.sym} 410 -900 3 0 {name=M47
L=\{L\}
W=\{W/2\}
body=VDD
nf=1
mult=1
ad="'int((nf+1)/2) * W/nf * 0.29'" 
pd="'2*int((nf+1)/2) * (W/nf + 0.29)'"
as="'int((nf+2)/2) * W/nf * 0.29'" 
ps="'2*int((nf+2)/2) * (W/nf + 0.29)'"
nrd="'0.29 / W'" nrs="'0.29 / W'"
sa=0 sb=0 sd=0
model=pfet_01v8
spiceprefix=X
}
C {madvlsi/pmos3.sym} 330 -900 3 0 {name=M48
L=\{L\}
W=\{W/2\}
body=VDD
nf=1
mult=1
ad="'int((nf+1)/2) * W/nf * 0.29'" 
pd="'2*int((nf+1)/2) * (W/nf + 0.29)'"
as="'int((nf+2)/2) * W/nf * 0.29'" 
ps="'2*int((nf+2)/2) * (W/nf + 0.29)'"
nrd="'0.29 / W'" nrs="'0.29 / W'"
sa=0 sb=0 sd=0
model=pfet_01v8
spiceprefix=X
}
C {madvlsi/nmos4.sym} 890 -670 1 0 {name=M49
L=\{L\}
W=\{W/2\}
nf=1 
mult=1
ad="'int((nf+1)/2) * W/nf * 0.29'" 
pd="'2*int((nf+1)/2) * (W/nf + 0.29)'"
as="'int((nf+2)/2) * W/nf * 0.29'" 
ps="'2*int((nf+2)/2) * (W/nf + 0.29)'"
nrd="'0.29 / W'" nrs="'0.29 / W'"
sa=0 sb=0 sd=0
model=nfet_01v8
spiceprefix=X
}
C {madvlsi/nmos3.sym} 970 -670 1 0 {name=M50
L=\{L\}
W=\{W/2\}
body=GND
nf=1
mult=1
ad="'int((nf+1)/2) * W/nf * 0.29'" 
pd="'2*int((nf+1)/2) * (W/nf + 0.29)'"
as="'int((nf+2)/2) * W/nf * 0.29'" 
ps="'2*int((nf+2)/2) * (W/nf + 0.29)'"
nrd="'0.29 / W'" nrs="'0.29 / W'"
sa=0 sb=0 sd=0
model=nfet_01v8
spiceprefix=X
}
C {madvlsi/nmos3.sym} 1050 -670 1 0 {name=M51
L=\{L\}
W=\{W/2\}
body=GND
nf=1
mult=1
ad="'int((nf+1)/2) * W/nf * 0.29'" 
pd="'2*int((nf+1)/2) * (W/nf + 0.29)'"
as="'int((nf+2)/2) * W/nf * 0.29'" 
ps="'2*int((nf+2)/2) * (W/nf + 0.29)'"
nrd="'0.29 / W'" nrs="'0.29 / W'"
sa=0 sb=0 sd=0
model=nfet_01v8
spiceprefix=X
}
C {madvlsi/nmos4.sym} 1130 -670 1 0 {name=M52
L=\{L\}
W=\{W/2\}
nf=1 
mult=1
ad="'int((nf+1)/2) * W/nf * 0.29'" 
pd="'2*int((nf+1)/2) * (W/nf + 0.29)'"
as="'int((nf+2)/2) * W/nf * 0.29'" 
ps="'2*int((nf+2)/2) * (W/nf + 0.29)'"
nrd="'0.29 / W'" nrs="'0.29 / W'"
sa=0 sb=0 sd=0
model=nfet_01v8
spiceprefix=X
}
C {madvlsi/gnd.sym} 1170 -650 0 0 {name=l7 lab=GND}
C {madvlsi/gnd.sym} -350 -560 0 0 {name=l8 lab=GND}
C {madvlsi/gnd.sym} 690 -560 0 0 {name=l9 lab=GND}
C {madvlsi/vdd.sym} 210 -1010 0 0 {name=l10 lab=VDD}
